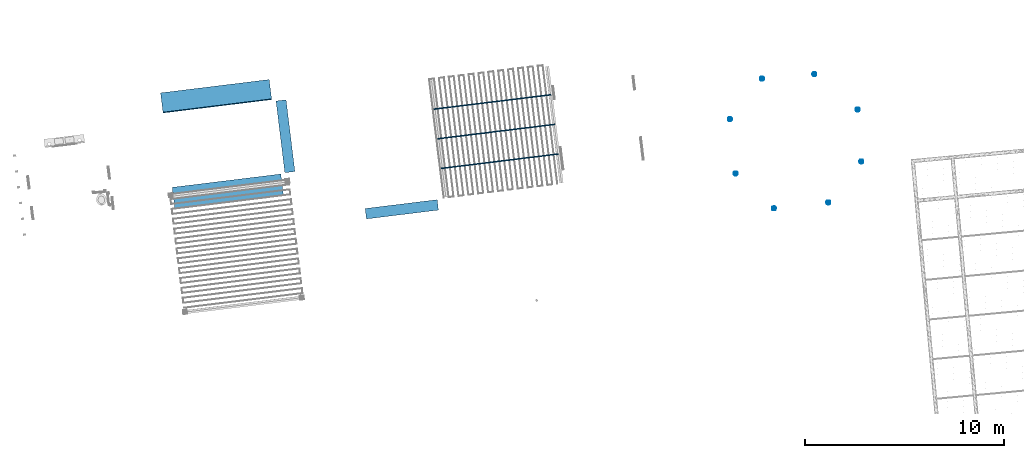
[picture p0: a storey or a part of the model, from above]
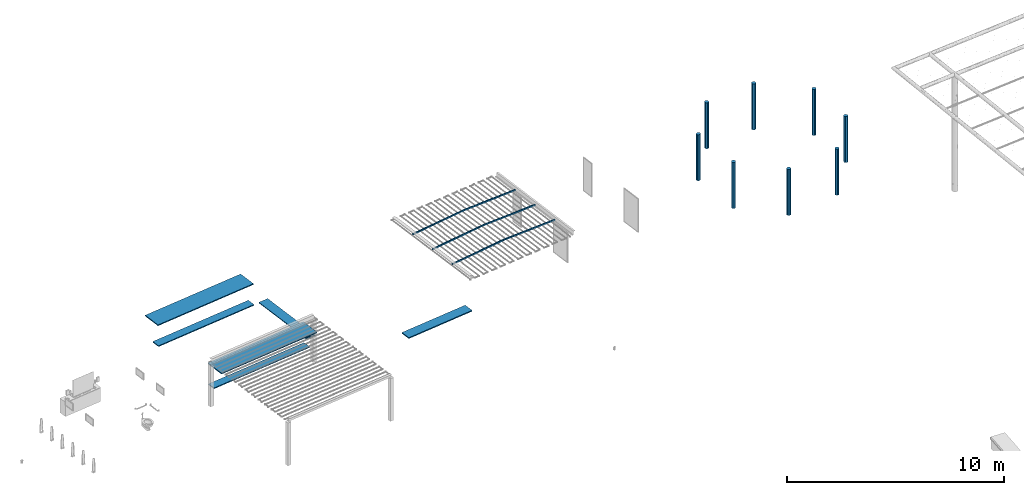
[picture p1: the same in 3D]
Properties of the parts of a building model (IFC2X3), part 1 of 2

# File
Description: ViewDefinition [CoordinationView_V2.0], RevitIdentifiers [VersionGUID: 33807b82-4eea-4ff3-baa8-d16956f95675, NumberOfSaves: 186], CoordinateReference [CoordinateBase: Coordenadas compartilhadas]
File name: JA_Taquaras_EP_R01.rvt
Time: 2023-06-01T09:59:46-03:00
Written by: ODA SDAI 23.12
Made in: Autodesk Revit 24.0.5.432 (PTB) - IFC 24.0.5.432

# IfcProject, JA_Taquaras_EP_R01.rvt
LongName: PROJETO EXECUTIVO; Phase: .

# IfcSite, Default
RefLatitude: -15, -52, 0, -120620; RefLongitude: -47, -55, 0, -114440; RefElevation: 0 m

# IfcBuilding, Projeto
LongName: Projeto
Pset_BuildingCommon - NumberOfStoreys: 5

# IfcBuildingStorey: Nível:8 mm Extremidade superior (5)
In: Projeto
Name | LongName | Elevation (m)
Nível 9 | Nível 9 | -2.58104
Nível 1 | Nível 1 | 0
Primeiro Pavimento | Primeiro Pavimento | 0
Segundo Pavimento | Segundo Pavimento | 3
Cobertura | Cobertura | 10

# IfcBeam: 23.25.30.11.14.14 - VIGA.MADEIRA:5x5 (8)
In: Nível 1
Type - Pset_BeamCommon - IsExternal: no; LoadBearing: yes
Material: .ET - EST METALICA
Pset_BeamCommon - Reference: 5x5; Span: 6 m; Slope: 0 deg
Pset_QuantityTakeOff - Reference: 5x5; sets with these values: 2
Name (23.25.30.11.14.14 - VIGA.MADEIRA:5x5:...)
1272677
1272681
1276401
1276405
1568845 | Group: Grupo de modelos:Grupo 6 (membros excluídos):1568625
1568847 | Group: Grupo de modelos:Grupo 6 (membros excluídos):1568625
1583513 | Group: Grupo de modelos:Grupo 6 (membros excluídos):1583293
1583515 | Group: Grupo de modelos:Grupo 6 (membros excluídos):1583293

# IfcBeam: 23.25.30.11.14.14 - VIGA.MADEIRA:5x5 2 (16)
Type - Pset_BeamCommon - IsExternal: no; LoadBearing: yes
Material: .ET - EST METALICA
Pset_BeamCommon - Reference: 5x5 2
Pset_QuantityTakeOff - Reference: 5x5 2; sets with these values: 2
Name (23.25.30.11.14.14 - VIGA.MADEIRA:5x5 2:...) | In | Span (m) | Slope (deg) | Group
1568901 | Primeiro Pavimento | 3 | 2.19526 | Grupo de modelos:Grupo 6 (membros excluídos):1568625
1568903 | Primeiro Pavimento | 3 | 2.19526 | Grupo de modelos:Grupo 6 (membros excluídos):1568625
1568905 | Primeiro Pavimento | 3 | 2.19526 | Grupo de modelos:Grupo 6 (membros excluídos):1568625
1568914 | Primeiro Pavimento | 3 | 2.19526 | Grupo de modelos:Grupo 6 (membros excluídos):1568625
1568916 | Primeiro Pavimento | 3 | 2.19526 | Grupo de modelos:Grupo 6 (membros excluídos):1568625
1568918 | Primeiro Pavimento | 3 | 2.19526 | Grupo de modelos:Grupo 6 (membros excluídos):1568625
1583569 | Nível 9 | 3 | 2.19526 | Grupo de modelos:Grupo 6 (membros excluídos):1583293
1583571 | Nível 9 | 3 | 2.19526 | Grupo de modelos:Grupo 6 (membros excluídos):1583293
1583573 | Nível 9 | 3 | 2.19526 | Grupo de modelos:Grupo 6 (membros excluídos):1583293
1583582 | Nível 9 | 3 | 2.19526 | Grupo de modelos:Grupo 6 (membros excluídos):1583293
1583584 | Nível 9 | 3 | 2.19526 | Grupo de modelos:Grupo 6 (membros excluídos):1583293
1583586 | Nível 9 | 3 | 2.19526 | Grupo de modelos:Grupo 6 (membros excluídos):1583293
1613297 | Nível 1 | 5.95047 | 0.0481941 | Grupo de modelos:Grupo 6 (membros excluídos):1568625
1613686 | Nível 1 | 5.95047 | 0.0481941 | Grupo de modelos:Grupo 6 (membros excluídos):1583293
1617300 | Nível 1 | 5.95047 | 0.0481941 | Grupo de modelos:Grupo 6 (membros excluídos):1568625
1617335 | Nível 1 | 5.95047 | 0.0481941 | Grupo de modelos:Grupo 6 (membros excluídos):1583293

# IfcBuildingElementProxy: Arvore simplificada:Arvore simplificada (20)
In: Nível 1
Type - Material: <Unnamed>
Pset_BuildingElementProxyCommon - Reference: Arvore simplificada; sets with these values: 2
Name (Arvore simplificada:Arvore simplificada:...)
1117187
1128409
1128419
1128431
1128439
1128447
1128455
1128463
1128471
1128479
1128489
1128499
1128509
1128519
1128527
1128539
1128549
1128559
1128567
1128575

# IfcBuildingElementProxy: DURAVIT_218209-DuraStyle-Basic-floor-mounted-toi:Vaso sanitário (4)
In: Nível 1
Type - Material: 218209-DuraStyle Basic floor-mounted toilet - durastyle-basic-floor-mounted-toilet-218209 - Color
Pset_BuildingElementProxyCommon - Reference: Vaso sanitário; sets with these values: 2
Name (DURAVIT_218209-DuraStyle-Basic-floor-mounted-toi:Vaso sanitário:...)
1442904
1442907
1442910
1442913

# IfcBuildingElementProxy: Dispositivos elétricos 1:Dispositivos elétricos 1, Dispositivos elétricos 1:Dispositivos elétricos 1:1149304
In: Nível 9
Type - Material: 3D Equip. 10
Pset_BuildingElementProxyCommon - Reference: Dispositivos elétricos 1; sets with these values: 2

# IfcBuildingElementProxy: Massa 1:Massa 1, Massa 1:Massa 1:1149017
In: Nível 9
Type - Material: <Unnamed>
Pset_BuildingElementProxyCommon - Reference: Massa 1; sets with these values: 2

# IfcBuildingElementProxy: Mobiliário 2:Mobiliário 2, Mobiliário 2:Mobiliário 2:1530271
In: Nível 9
Type - Material: cacao
Pset_BuildingElementProxyCommon - Reference: Mobiliário 2; sets with these values: 2

# IfcBuildingElementProxy: Modelos genéricos 1:Modelos genéricos 1, Modelos genéricos 1:Modelos genéricos 1:1151902
In: Nível 9
Type - Material: metal estrutura
Pset_BuildingElementProxyCommon - Reference: Modelos genéricos 1; sets with these values: 2

# IfcBuildingElementProxy: Modelos genéricos 2:Modelos genéricos 2, Modelos genéricos 2:Modelos genéricos 2:1620208
In: Nível 9
Type - Material: .ET - EST METALICA
Pset_BuildingElementProxyCommon - Reference: Modelos genéricos 2; sets with these values: 2
Pset_ProvisionForVoid - Width: 0.19 m; Height: 0.192261 m; Depth: 0.192261 m

# IfcBuildingElementProxy: Modelos genéricos 3:Modelos genéricos 3, Modelos genéricos 3:Modelos genéricos 3:1680973
In: Nível 9
Type - Material: Vidro
Pset_BuildingElementProxyCommon - Reference: Modelos genéricos 3; sets with these values: 2
Pset_ProvisionForVoid - Width: 0.005 m; Height: 1.2 m; Depth: 1.2 m

# IfcBuildingElementProxy: Vegetação Genérica:Árvore (21)
Type - Material: Tronco, Vegetação
Pset_BuildingElementProxyCommon - Reference: Árvore; sets with these values: 2
Name (Vegetação Genérica:Árvore:...) | In
1433401 | Nível 1
1433469 | Nível 1
1433492 | Nível 1
1433971 | Nível 1
1434128 | Nível 1
1434138 | Nível 1
1434273 | Nível 1
1434547 | Nível 1
1434555 | Nível 1
1434704 | Nível 1
1434777 | Nível 1
1434796 | Nível 1
1434824 | Nível 1
1434863 | Nível 1
1434968 | Nível 1
1435148 | Nível 1
1435156 | Nível 1
1461229 | Nível 1
1461309 | Nível 1
1474241 | Nível 1
1711147 | Primeiro Pavimento

# IfcColumn: Coreto:Coreto, Coreto:Coreto:1116822
In: Nível 9
Type - PredefinedType: COLUMN; Material: <Unnamed>, Cerejeira
Type - Pset_ColumnCommon - IsExternal: no; LoadBearing: yes
Material: Cerejeira
Pset_ColumnCommon - Reference: Coreto
Pset_QuantityTakeOff - Reference: Coreto; sets with these values: 2

# IfcCovering: Forro composto:Plano (4)
In: Segundo Pavimento
Type - PredefinedType: CEILING
Type - Pset_CoveringCommon - TotalThickness: 0.057 m
Material: Camada de suporte de metal 0.045 m, Placa de gesso de parede 0.012 m
Pset_CoveringCommon - Reference: Plano; sets with these values: 2
Name (Forro composto:Plano:...) | Group
1095109 | Grupo de modelos:ED1:1098709
1104618 | Grupo de modelos:ED6:1103990
1104683 | Grupo de modelos:ED6:1103990
1105033 | Grupo de modelos:ED6:1103990

# IfcCurtainWall: Parede cortina:Vitrine (5)
In: Nível 1
Type - Pset_CurtainWallCommon - IsExternal: yes
Pset_CurtainWallCommon - Reference: Vitrine
Pset_QuantityTakeOff - Reference: Vitrine
Name (Parede cortina:Vitrine:...)
1573662 | Group: Grupo de modelos:quiosque3:1573406
1574445
1596405
1626986
1627316

# IfcDistributionPort (15)
Description: Flow
Name | FlowDirection
InPort_1444392_1 | SINK
OutPort_1444392_2 | SOURCE
InPort_1675223_5 | SINK
OutPort_1675223_6 | SOURCE
InPort_1675503_5 | SINK
OutPort_1675503_6 | SOURCE
InPort_1675512_5 | SINK
OutPort_1675512_6 | SOURCE
InPort_1675577_5 | SINK
OutPort_1675577_6 | SOURCE
InPort_1675769_5 | SINK
OutPort_1675769_6 | SOURCE
InPort_1680600_1 | SINK
InPort_1680650_1 | SINK
InPort_1746563_1 | SINK

# IfcDoor: M_Folha única:0800 x 2100mm, M_Folha única:0800 x 2100mm:1297596
In: Nível 1
Type - ParameterTakesPrecedence: no; Sizeable: no; Material: Porta - Batente, Porta - Painel
Type - Pset_DoorCommon - IsExternal: no; ThermalTransmittance: 3.7021 kg/K/s3
OverallHeight: 2.1 m; OverallWidth: 0.8 m
Pset_DoorCommon - Reference: 0800 x 2100mm
Pset_QuantityTakeOff - Reference: 0800 x 2100mm

# IfcDoor: M_Folha única:0915 x 2032mm, M_Folha única:0915 x 2032mm:1300241
In: Nível 1
Type - ParameterTakesPrecedence: no; Sizeable: no; Material: Porta - Batente, Porta - Painel
Type - Pset_DoorCommon - IsExternal: no; ThermalTransmittance: 3.7021 kg/K/s3
OverallHeight: 2.032 m; OverallWidth: 0.915 m
Pset_DoorCommon - Reference: 0915 x 2032mm
Pset_QuantityTakeOff - Reference: 0915 x 2032mm

# IfcDoor: M_porta pvc:0800 x 2100mm (4)
In: Nível 1
Type - ParameterTakesPrecedence: no; Sizeable: no; Material: Porta - Batente, Porta - Painel
Type - Pset_DoorCommon - IsExternal: no; ThermalTransmittance: 3.7021 kg/K/s3
OverallHeight: 2.1 m; OverallWidth: 0.8 m
Pset_DoorCommon - Reference: 0800 x 2100mm
Pset_QuantityTakeOff - Reference: 0800 x 2100mm
Name (M_porta pvc:0800 x 2100mm:...)
1306554
1306905
1306987
1306988

# IfcElementAssembly: Sistema de viga estrutural:Sistema de estrutura estrutural (4)
PredefinedType: BEAM_GRID
Pset_QuantityTakeOff - Reference: Sistema de estrutura estrutural
Name (Sistema de viga estrutural:Sistema de estrutura estrutural:...) | In | Group
1568896 | Primeiro Pavimento | Grupo de modelos:Grupo 6 (membros excluídos):1568625
1568909 | Primeiro Pavimento | Grupo de modelos:Grupo 6 (membros excluídos):1568625
1583564 | Nível 9 | Grupo de modelos:Grupo 6 (membros excluídos):1583293
1583577 | Nível 9 | Grupo de modelos:Grupo 6 (membros excluídos):1583293

# IfcFlowTerminal: Deca_Bacia Duna_P.707_Caixa Acoplada:Dual Flux 3 lpf / 6 lpf - Branco GE17 (5)
In: Nível 1
Type - Material: <Unnamed>, Deca GE17 Branco Gelo Cerâmica
Type - Pset_ManufacturerTypeInformation - Manufacturer: Deca
Pset_DistributionFlowElementCommon - Reference: Dual Flux 3 lpf / 6 lpf - Branco GE17; sets with these values: 2
Name (Deca_Bacia Duna_P.707_Caixa Acoplada:Dual Flux 3 lpf / 6 lpf - Branco GE17:...)
1675223
1675503
1675512
1675577
1675769

# IfcFlowTerminal: Deca_Shared_Assento_P.707:Assento termofixo slow close e easy clean - Branco GE17 (5)
In: Nível 1
Type - Material: Deca GE17 Branco Gelo Poliéster
Type - Pset_ManufacturerTypeInformation - Manufacturer: Deca
Pset_DistributionFlowElementCommon - Reference: Assento termofixo slow close e easy clean - Branco GE17; sets with these values: 2
Name (Deca_Shared_Assento_P.707:Assento termofixo slow close e easy clean - Branco GE17:...)
1675224
1675504
1675513
1675578
1675770

# IfcFlowTerminal: Deca_Shared_Caixa Acoplada_P.707:Dual Flux 3 lpf / 6 lpf - Branco GE17 (5)
In: Nível 1
Type - Material: Deca GE17 Branco Gelo Cerâmica
Type - Pset_ManufacturerTypeInformation - Manufacturer: Deca
Pset_DistributionFlowElementCommon - Reference: Dual Flux 3 lpf / 6 lpf - Branco GE17; sets with these values: 2
Name (Deca_Shared_Caixa Acoplada_P.707:Dual Flux 3 lpf / 6 lpf - Branco GE17:...)
1675225
1675505
1675514
1675579
1675771

# IfcFlowTerminal: Deca_Torneira_Link_1167.C.LNK:1167.C.LNK (3)
Type - Material: Deca CR10 Cromado Metal
Type - Pset_ManufacturerTypeInformation - Manufacturer: Deca
Pset_DistributionFlowElementCommon - Reference: 1167.C.LNK; sets with these values: 2
Name (Deca_Torneira_Link_1167.C.LNK:1167.C.LNK:...) | In
1680600 | Cobertura
1680650 | Cobertura
1746563 | Nível 1

# IfcFlowTerminal: M_Pia de cozinha-Ilha:Pia para banheiro (3)
In: Nível 1
Type - Material: Metal - Aço, Polido
Pset_DistributionFlowElementCommon - Reference: Pia para banheiro; sets with these values: 2
Name (M_Pia de cozinha-Ilha:Pia para banheiro:...)
1440380
1440467
1440518

# IfcFlowTerminal: Plumbing-Gravity-Toilets-Sloan-Valve-WETS-40294211:Vaso sanitário PNE, Plumbing-Gravity-Toilets-Sloan-Valve-WETS-40294211:Vaso sanitário PNE:1444392
In: Nível 1
Type - Material: Sloan Valve - Vitreous China - White, Sloan Valve - Finish - Polished Chrome
Type - Pset_ManufacturerTypeInformation - Manufacturer: Sloan Valve
Classification: D2010 Uniformat (Uniformat)
Pset_DistributionFlowElementCommon - Reference: Vaso sanitário PNE; sets with these values: 2

# IfcFlowTerminal: Sanitary_Basins_DURAVIT_236375-Sink:Pia adaptada PNE, Sanitary_Basins_DURAVIT_236375-Sink:Pia adaptada PNE:1441920
In: Nível 1
Type - Material: 236375 Sink - white-tulip-sink-236375 - White Alpin
Pset_DistributionFlowElementCommon - Reference: Pia adaptada PNE; sets with these values: 2

# IfcFlowTerminal: UK_Grab Rail Horizontal:2D Disabled Toilet (2)
In: Nível 9
Type - Material: Metal - White powder coated
Pset_DistributionFlowElementCommon - Reference: 2D Disabled Toilet; sets with these values: 2
Name (UK_Grab Rail Horizontal:2D Disabled Toilet:...)
1665409
1665930

# IfcFlowTerminal: Vigas2:Vigas, Vigas2:Vigas:1583611
In: Nível 9
Type - Material: .ET - EST METALICA
Pset_DistributionFlowElementCommon - Reference: Vigas; sets with these values: 2
Group: Grupo de modelos:Grupo 6 (membros excluídos):1583293

# IfcFlowTerminal: Vigas3:Vigas, Vigas3:Vigas:1583635
In: Nível 9
Type - Material: .ET - EST METALICA
Pset_DistributionFlowElementCommon - Reference: Vigas; sets with these values: 2
Group: Grupo de modelos:Grupo 6 (membros excluídos):1583293

# IfcFlowTerminal: Vigas4:Vigas, Vigas4:Vigas:1568943
In: Nível 9
Type - Material: .ET - EST METALICA
Pset_DistributionFlowElementCommon - Reference: Vigas; sets with these values: 2
Group: Grupo de modelos:Grupo 6 (membros excluídos):1568625

# IfcFlowTerminal: Vigas5:Vigas, Vigas5:Vigas:1568967
In: Nível 9
Type - Material: .ET - EST METALICA
Pset_DistributionFlowElementCommon - Reference: Vigas; sets with these values: 2
Group: Grupo de modelos:Grupo 6 (membros excluídos):1568625

# IfcFlowTerminal: _Produtos_Arq_Bib_Floor_mounted_flush-valve_toilet_w_3-piece_grab_bars_4834:17" Seat Height, _Produtos_Arq_Bib_Floor_mounted_flush-valve_toilet_w_3-piece_grab_bars_4834:17" Seat Height:1669619
In: Nível 9
Type - Material: Porcelain - Ivory, Laminate - Ivory,Matte, Metal - Steel, Polished
Classification: D2010110 Uniformat (Uniformat)
Pset_DistributionFlowElementCommon - Reference: 17" Seat Height; sets with these values: 2

# IfcFurnishingElement: Bancadas banheiro2:Bancadas banheiro, Bancadas banheiro2:Bancadas banheiro:1681031
In: Nível 9
Type - Material: Plastico preto fosco, Aço, GRANITO, Madeira ripada
Pset_QuantityTakeOff - Reference: Bancadas banheiro

# IfcFurnishingElement: Banco2:Banco com encosto 2, Banco2:Banco com encosto 2:1472425
In: Nível 1
Type - Material: Metal, Madeira
Type - Pset_ManufacturerTypeInformation - Manufacturer: MMcité
Pset_QuantityTakeOff - Reference: Banco com encosto 2

# IfcFurnishingElement: CADEIRAADIRONDAQUE:Adirondack Chair (24)
In: Nível 1
Type - Material: NewTechWood - Antique Atlantic
Type - Pset_ManufacturerTypeInformation - Manufacturer: NewTechWood
Pset_QuantityTakeOff - Reference: Adirondack Chair
Name (CADEIRAADIRONDAQUE:Adirondack Chair:...)
1426978
1427038
1427043
1427048
1427064
1427069
1427074
1427079
1427092
1427099
1427104
1427109
1514125 | Group: Grupo de modelos:Grupo de matrizes 3:1514393
1514407 | Group: Grupo de modelos:Grupo de matrizes 3:1514408
1514420 | Group: Grupo de modelos:Grupo de matrizes 3:1514421
1514458 | Group: Grupo de modelos:Grupo de matrizes 3:1514459
1514460 | Group: Grupo de modelos:Grupo de matrizes 3:1514461
1514462 | Group: Grupo de modelos:Grupo de matrizes 3:1514463
1514476 | Group: Grupo de modelos:Grupo de matrizes 3:1514477
1514478 | Group: Grupo de modelos:Grupo de matrizes 3:1514479
1514480 | Group: Grupo de modelos:Grupo de matrizes 3:1514481
1514494 | Group: Grupo de modelos:Grupo de matrizes 3:1514495
1514496 | Group: Grupo de modelos:Grupo de matrizes 3:1514497
1514498 | Group: Grupo de modelos:Grupo de matrizes 3:1514499

# IfcFurnishingElement: CS110:Lixeira Simples (6)
In: Nível 1
Type - Material: Metal, Aço, Metal(1)
Type - Pset_ManufacturerTypeInformation - Manufacturer: MMcité
Pset_QuantityTakeOff - Reference: Lixeira Simples
Name (CS110:Lixeira Simples:...)
1444702
1444705
1444708
1472524
1473167
1473223

# IfcFurnishingElement: Iluminação de chão:Iluminação de chão (19)
Type - Material: Aço, <Unnamed>
Pset_QuantityTakeOff - Reference: Iluminação de chão
Name (Iluminação de chão:Iluminação de chão:...) | In
1435394 | Nível 1
1436348 | Nível 1
1437167 | Nível 9
1437235 | Nível 1
1437324 | Nível 1
1437332 | Nível 1
1437391 | Nível 1
1437732 | Nível 9
1437844 | Nível 1
1438212 | Nível 9
1438383 | Nível 1
1438557 | Nível 1
1438599 | Nível 1
1438659 | Nível 9
1438667 | Nível 1
1438708 | Nível 9
1438717 | Nível 1
1461230 | Nível 9
1461311 | Nível 9

# IfcFurnishingElement: Landscaping_Other_Byarums-Bruk_Arkus:Biciletário (12)
Type - Material: ByarumsBruk-Natur(RawAluminium)
Type - Pset_ElementShading - Color: Grey
Type - Pset_ManufacturerTypeInformation - ModelReference: n/a; Manufacturer: Byarums Bruk
Type - Pset_ProductRequirements - Name: Byarums-Bruk_Arkus; Category: Cycle stands and lockers
Pset_ManufacturerOccurrence - BarCode: n/a; SerialNumber: n/a
Pset_QuantityTakeOff - Reference: Biciletário
Name (Landscaping_Other_Byarums-Bruk_Arkus:Biciletário:...) | In
1444721 | Nível 1
1444752 | Nível 1
1444760 | Nível 1
1444768 | Nível 1
1444776 | Nível 1
1444784 | Nível 1
1472692 | Nível 9
1472823 | Nível 9
1472833 | Nível 9
1472843 | Nível 9
1472851 | Nível 9
1472859 | Nível 9

# IfcFurnishingElement: Mobiliário 1:Mobiliário 1, Mobiliário 1:Mobiliário 1:1150153
In: Primeiro Pavimento
Type - Material: 3D Mecanismo 01 Equip. 02
Pset_QuantityTakeOff - Reference: Mobiliário 1

# IfcFurnishingElement: Mobiliário 3:Mobiliário 2, Mobiliário 3:Mobiliário 2:1530515
In: Nível 9
Type - Material: Camada de suporte de metal
Pset_QuantityTakeOff - Reference: Mobiliário 2

# IfcFurnishingElement: Mobiliário 4:Mobiliário 2, Mobiliário 4:Mobiliário 2:1530638
In: Nível 9
Type - Material: Camada de suporte de metal, cacao
Pset_QuantityTakeOff - Reference: Mobiliário 2

# IfcFurnishingElement: Pergolado2:Pergolado, Pergolado2:Pergolado:1616212
In: Nível 9
Type - Material: Aço
Pset_QuantityTakeOff - Reference: Pergolado
Group: Grupo de modelos:Grupo 6 (membros excluídos):1583293

# IfcFurnishingElement: Pergolado3:Pergolado, Pergolado3:Pergolado:1615888
In: Nível 9
Type - Material: Aço
Pset_QuantityTakeOff - Reference: Pergolado
Group: Grupo de modelos:Grupo 6 (membros excluídos):1568625

# IfcFurnishingElement: lareiran:lareiran (3)
In: Nível 1
Type - Material: <Unnamed>
Pset_QuantityTakeOff - Reference: lareiran
Name (lareiran:lareiran:...)
1417715
1417724
1417743

# IfcFurnishingElement: play genérico:play genérico, play genérico:play genérico:1318031
In: Nível 1
Type - Material: <Unnamed>
Pset_QuantityTakeOff - Reference: play genérico

# IfcFurnishingElement: poste ja8:poste ja8 (7)
In: Nível 1
Type - Material: <Unnamed>
Pset_QuantityTakeOff - Reference: poste ja8
Name (poste ja8:poste ja8:...)
1460368
1460384
1460458
1461030
1461407
1461445
1461491

# IfcMember: Montante retangular:50 x 150mm (110)
In: Nível 1
Type - PredefinedType: MULLION; Material: Alumín.
Type - Pset_MemberCommon - IsExternal: no
Pset_MemberCommon - Reference: 50 x 150mm
Pset_QuantityTakeOff - Reference: 50 x 150mm
Name (Montante retangular:50 x 150mm:...) | Span (m)
1573681 | 0.833761 | Pset_MemberCommon - IsExternal: yes; Group: Grupo de modelos:quiosque3:1573406
1573682 | 0.858761 | Pset_MemberCommon - IsExternal: yes; Group: Grupo de modelos:quiosque3:1573406
1573683 | 0.858761 | Pset_MemberCommon - IsExternal: yes; Group: Grupo de modelos:quiosque3:1573406
1573686 | 2.18297 | Pset_MemberCommon - IsExternal: yes; Group: Grupo de modelos:quiosque3:1573406
1573687 | 2.18297 | Pset_MemberCommon - IsExternal: yes; Group: Grupo de modelos:quiosque3:1573406
1573694 | 0.653049 | Pset_MemberCommon - IsExternal: yes; Group: Grupo de modelos:quiosque3:1573406
1573695 | 1.14182 | Pset_MemberCommon - IsExternal: yes; Group: Grupo de modelos:quiosque3:1573406
1573696 | 0.833761 | Pset_MemberCommon - IsExternal: yes; Group: Grupo de modelos:quiosque3:1573406
1573697 | 0.858761 | Pset_MemberCommon - IsExternal: yes; Group: Grupo de modelos:quiosque3:1573406
1573698 | 0.858761 | Pset_MemberCommon - IsExternal: yes; Group: Grupo de modelos:quiosque3:1573406
1573747 | 0.833761 | Pset_MemberCommon - IsExternal: yes; Group: Grupo de modelos:quiosque3:1573406
1573748 | 0.833761 | Pset_MemberCommon - IsExternal: yes; Group: Grupo de modelos:quiosque3:1573406
1573749 | 2.18297 | Pset_MemberCommon - IsExternal: yes; Group: Grupo de modelos:quiosque3:1573406
1573750 | 0.645326 | Pset_MemberCommon - IsExternal: yes; Group: Grupo de modelos:quiosque3:1573406
1582803 | 1.02924 | Pset_MemberCommon - IsExternal: yes; Group: Grupo de modelos:quiosque3:1573406
1582804 | 1.02101 | Pset_MemberCommon - IsExternal: yes; Group: Grupo de modelos:quiosque3:1573406
1582805 | 1.02924 | Pset_MemberCommon - IsExternal: yes; Group: Grupo de modelos:quiosque3:1573406
1582806 | 1.05755 | Pset_MemberCommon - IsExternal: yes; Group: Grupo de modelos:quiosque3:1573406
1582807 | 2.18297 | Pset_MemberCommon - IsExternal: yes; Group: Grupo de modelos:quiosque3:1573406
1582809 | 0.169852 | Pset_MemberCommon - IsExternal: yes; Group: Grupo de modelos:quiosque3:1573406
1626107 | 0.162129 | Pset_MemberCommon - IsExternal: yes; Group: Grupo de modelos:quiosque3:1573406
1626108 | 2.18297 | Pset_MemberCommon - IsExternal: yes; Group: Grupo de modelos:quiosque3:1573406
1574464 | 0.833761
1574465 | 0.858761
1574466 | 0.858761
1574469 | 2.18297
1574470 | 2.18297
1574477 | 0.653049
1574478 | 1.14182
1574479 | 0.833761
1574480 | 0.858761
1574481 | 0.858761
1574493 | 0.833761
1574494 | 0.833761
1574495 | 2.18297
1574496 | 0.645326
1582627 | 1.02924
1582628 | 1.02101
1582629 | 1.02924
1582630 | 1.05755
1582631 | 2.18297
1582633 | 0.169852
1626023 | 0.162129
1626024 | 2.18297
1596418 | 0.833761
1596419 | 0.858761
1596420 | 0.858761
1596421 | 2.20797
1596422 | 2.20797
1596427 | 0.653049
1596428 | 1.14182
1596429 | 0.833761
1596430 | 0.858761
1596431 | 0.858761
1596467 | 0.833761
1596468 | 0.833761
1596469 | 2.20797
1596470 | 0.645326
1596475 | 1.02924
1596476 | 1.02101
1596477 | 1.02924
1596478 | 1.05755
1596479 | 2.20797
1596481 | 0.169852
1626013 | 0.162129
1626014 | 2.20797
1626999 | 0.833761
1627000 | 0.858761
1627001 | 0.858761
1627002 | 2.18297
1627003 | 2.18297
1627008 | 0.653049
1627009 | 1.14182
1627010 | 0.833761
1627011 | 0.858761
1627012 | 0.858761
1627016 | 0.833761
1627017 | 0.833761
1627018 | 2.18297
1627019 | 0.645326
1627024 | 1.02924
1627025 | 1.02101
1627026 | 1.02924
1627027 | 1.05755
1627028 | 2.18297
1627029 | 0.169852
1627030 | 0.162129
1627031 | 2.18297
1627329 | 0.833761
1627330 | 0.858761
1627331 | 0.858761
1627332 | 2.18297
1627333 | 2.18297
1627338 | 0.653049
1627339 | 1.14182
1627340 | 0.833761
1627341 | 0.858761
1627342 | 0.858761
1627346 | 0.833761
1627347 | 0.833761
1627348 | 2.18297
1627349 | 0.645326
1627354 | 1.02924
1627355 | 1.02101
1627356 | 1.02924
1627357 | 1.05755
1627358 | 2.18297
1627359 | 0.169852
1627360 | 0.162129
1627361 | 2.18297

# IfcOpeningElement: Opening (265)
In: Nível 1
Name | Reference | sets with these values
Parede básica:JA_Aluminio:1095195:1 | JA_Aluminio | 2 | Group: Grupo de modelos:ED1:1098709
Parede básica:JA_Aluminio:1095199:1 | JA_Aluminio | 2 | Group: Grupo de modelos:ED1:1098709
Parede básica:JA_Aluminio:1095203:1 | JA_Aluminio | 2 | Group: Grupo de modelos:ED1:1098709
Parede básica:JA_Aluminio:1095207:1 | JA_Aluminio | 2 | Group: Grupo de modelos:ED1:1098709
Parede básica:JA_Aluminio:1095211:1 | JA_Aluminio | 2 | Group: Grupo de modelos:ED1:1098709
Parede básica:JA_Aluminio:1095215:1 | JA_Aluminio | 2 | Group: Grupo de modelos:ED1:1098709
Parede básica:JA_Aluminio:1095229:1 | JA_Aluminio | 2 | Group: Grupo de modelos:ED1:1098709
Parede básica:JA_Aluminio:1095233:1 | JA_Aluminio | 2 | Group: Grupo de modelos:ED1:1098709
Parede básica:JA_Aluminio:1095237:1 | JA_Aluminio | 2 | Group: Grupo de modelos:ED1:1098709
Parede básica:JA_Aluminio:1095241:1 | JA_Aluminio | 2 | Group: Grupo de modelos:ED1:1098709
Parede básica:JA_Aluminio:1095251:1 | JA_Aluminio | 2 | Group: Grupo de modelos:ED1:1098709
2 x Parede básica:JA_Aluminio:713331 | JA_Aluminio | 2 | Group: Grupo de modelos:ED6:1103990
Parede básica:JA_Aluminio:1104897:1 | JA_Aluminio | 2 | Group: Grupo de modelos:ED6:1103990
Parede básica:JA_Aluminio:1104898:1 | JA_Aluminio | 2 | Group: Grupo de modelos:ED6:1103990
Parede básica:JA_Aluminio:1104899:1 | JA_Aluminio | 2 | Group: Grupo de modelos:ED6:1103990
Parede básica:JA_Aluminio:1104900:1 | JA_Aluminio | 2 | Group: Grupo de modelos:ED6:1103990
Parede básica:JA_Aluminio:1104901:1 | JA_Aluminio | 2 | Group: Grupo de modelos:ED6:1103990
Parede básica:JA_Aluminio:1104902:1 | JA_Aluminio | 2 | Group: Grupo de modelos:ED6:1103990
Parede básica:JA_Aluminio:1104903:1 | JA_Aluminio | 2 | Group: Grupo de modelos:ED6:1103990
Parede básica:JA_Aluminio:1104904:1 | JA_Aluminio | 2 | Group: Grupo de modelos:ED6:1103990
Parede básica:JA_Aluminio:1104905:1 | JA_Aluminio | 2 | Group: Grupo de modelos:ED6:1103990
Parede básica:JA_Aluminio:1104906:1 | JA_Aluminio | 2 | Group: Grupo de modelos:ED6:1103990
Parede básica:15cm:1105429:1 | 15cm | 2 | Group: Grupo de modelos:ED4:1105388
Parede básica:15cm:1105430:1 | 15cm | 2 | Group: Grupo de modelos:ED4:1105388
Parede básica:15cm:1105431:1 | 15cm | 2 | Group: Grupo de modelos:ED4:1105388
Parede básica:15cm:1105434:1 | 15cm | 2 | Group: Grupo de modelos:ED4:1105388
11 x Piso:Basalto 40x80:1313126 | Basalto 40x80 | 2
Parede básica:15cm 2:1179894:1 | 15cm 2 | 2
Parede básica:15cm 2:1179894:2 | 15cm 2 | 2
Parede básica:15cm 2:1179894:3 | 15cm 2 | 2
Parede básica:15cm 2:1179894:4 | 15cm 2 | 2
Parede básica:15cm 2:1179894:5 | 15cm 2 | 2
Parede básica:15cm 2:1179894:6 | 15cm 2 | 2
Parede básica:15cm 2:1179894:7 | 15cm 2 | 2
Parede básica:15cm 2:1179894:8 | 15cm 2 | 2
Parede básica:15cm 2:1179894:9 | 15cm 2 | 2
Parede básica:15cm 2:1179894:10 | 15cm 2 | 2
Parede básica:15cm 2:1179894:11 | 15cm 2 | 2
Parede básica:15cm 2:1179894:12 | 15cm 2 | 2
Parede básica:15cm 2:1179894:13 | 15cm 2 | 2
Parede básica:15cm 2:1179894:14 | 15cm 2 | 2
Parede básica:15cm 2:1179894:15 | 15cm 2 | 2
Parede básica:15cm 2:1179894:16 | 15cm 2 | 2
Parede básica:15cm 2:1179894:17 | 15cm 2 | 2
Parede básica:15cm 2:1179894:18 | 15cm 2 | 2
Parede básica:15cm 2:1179894:19 | 15cm 2 | 2
Parede básica:15cm 2:1179894:20 | 15cm 2 | 2
Parede básica:15cm 2:1179894:21 | 15cm 2 | 2
Parede básica:15cm 2:1179894:22 | 15cm 2 | 2
Parede básica:15cm 2:1179894:23 | 15cm 2 | 2
Parede básica:15cm 2:1179894:24 | 15cm 2 | 2
Parede básica:15cm 2:1179894:25 | 15cm 2 | 2
Parede básica:15cm 2:1179894:26 | 15cm 2 | 2
Parede básica:15cm 2:1179894:27 | 15cm 2 | 2
Parede básica:15cm 2:1179943:1 | 15cm 2 | 2
Parede básica:15cm 2:1179943:2 | 15cm 2 | 2
Parede básica:15cm 2:1179943:3 | 15cm 2 | 2
Parede básica:15cm 2:1179943:4 | 15cm 2 | 2
Parede básica:15cm 2:1179943:5 | 15cm 2 | 2
Parede básica:15cm 2:1179943:6 | 15cm 2 | 2
Parede básica:15cm 2:1179943:7 | 15cm 2 | 2
Parede básica:15cm 2:1179943:8 | 15cm 2 | 2
Parede básica:15cm 2:1179943:9 | 15cm 2 | 2
Parede básica:15cm 2:1179943:10 | 15cm 2 | 2
Parede básica:15cm 2:1179943:11 | 15cm 2 | 2
Parede básica:15cm 2:1179943:12 | 15cm 2 | 2
Parede básica:15cm 2:1179943:13 | 15cm 2 | 2
Parede básica:15cm 2:1179943:14 | 15cm 2 | 2
Parede básica:15cm 2:1179943:15 | 15cm 2 | 2
Parede básica:15cm 2:1179943:16 | 15cm 2 | 2
Parede básica:15cm 2:1179943:17 | 15cm 2 | 2
Parede básica:15cm 2:1179943:18 | 15cm 2 | 2
Parede básica:15cm 2:1179943:19 | 15cm 2 | 2
Parede básica:15cm 2:1179943:20 | 15cm 2 | 2
Parede básica:15cm 2:1179943:21 | 15cm 2 | 2
Parede básica:15cm 2:1179943:22 | 15cm 2 | 2
Parede básica:15cm 2:1179943:23 | 15cm 2 | 2
Parede básica:15cm 2:1179943:24 | 15cm 2 | 2
Parede básica:15cm 2:1179943:25 | 15cm 2 | 2
Parede básica:15cm 2:1179943:26 | 15cm 2 | 2
Parede básica:15cm 2:1179943:27 | 15cm 2 | 2
Parede básica:15cm 2:1180014:1 | 15cm 2 | 2
Parede básica:15cm 2:1180014:2 | 15cm 2 | 2
Parede básica:15cm 2:1180014:3 | 15cm 2 | 2
Parede básica:15cm 2:1180014:4 | 15cm 2 | 2
Parede básica:15cm 2:1180014:5 | 15cm 2 | 2
Parede básica:15cm 2:1180014:6 | 15cm 2 | 2
Parede básica:15cm 2:1180014:7 | 15cm 2 | 2
Parede básica:15cm 2:1180014:8 | 15cm 2 | 2
Parede básica:15cm 2:1180014:9 | 15cm 2 | 2
Parede básica:15cm 2:1180014:10 | 15cm 2 | 2
Parede básica:15cm 2:1180014:11 | 15cm 2 | 2
Parede básica:15cm 2:1180014:12 | 15cm 2 | 2
Parede básica:15cm 2:1180014:13 | 15cm 2 | 2
Parede básica:15cm 2:1180014:14 | 15cm 2 | 2
Parede básica:15cm 2:1180014:15 | 15cm 2 | 2
Parede básica:15cm 2:1180014:16 | 15cm 2 | 2
Parede básica:15cm 2:1180014:17 | 15cm 2 | 2
Parede básica:15cm 2:1180014:18 | 15cm 2 | 2
Parede básica:15cm 2:1180014:19 | 15cm 2 | 2
Parede básica:15cm 2:1180014:20 | 15cm 2 | 2
Parede básica:15cm 2:1180014:21 | 15cm 2 | 2
Parede básica:15cm 2:1180014:22 | 15cm 2 | 2
Parede básica:15cm 2:1180014:23 | 15cm 2 | 2
Parede básica:15cm 2:1180014:24 | 15cm 2 | 2
Parede básica:15cm 2:1180014:25 | 15cm 2 | 2
Parede básica:15cm 2:1180014:26 | 15cm 2 | 2
Parede básica:15cm 2:1180014:27 | 15cm 2 | 2
Parede básica:15cm 2:1180143:1 | 15cm 2 | 2
Parede básica:15cm 2:1180143:2 | 15cm 2 | 2
Parede básica:15cm 2:1180143:3 | 15cm 2 | 2
Parede básica:15cm 2:1180143:4 | 15cm 2 | 2
Parede básica:15cm 2:1180143:5 | 15cm 2 | 2
Parede básica:15cm 2:1180143:6 | 15cm 2 | 2
Parede básica:15cm 2:1180143:7 | 15cm 2 | 2
Parede básica:15cm 2:1180143:8 | 15cm 2 | 2
Parede básica:15cm 2:1180143:9 | 15cm 2 | 2
Parede básica:15cm 2:1180143:10 | 15cm 2 | 2
Parede básica:15cm 2:1180143:11 | 15cm 2 | 2
Parede básica:15cm 2:1180143:12 | 15cm 2 | 2
Parede básica:15cm 2:1180143:13 | 15cm 2 | 2
Parede básica:15cm 2:1180143:14 | 15cm 2 | 2
Parede básica:15cm 2:1180143:15 | 15cm 2 | 2
Parede básica:15cm 2:1180143:16 | 15cm 2 | 2
Parede básica:15cm 2:1180143:17 | 15cm 2 | 2
Parede básica:15cm 2:1180143:18 | 15cm 2 | 2
Parede básica:15cm 2:1180143:19 | 15cm 2 | 2
Parede básica:15cm 2:1180143:20 | 15cm 2 | 2
Parede básica:15cm 2:1180143:21 | 15cm 2 | 2
Parede básica:15cm 2:1180143:22 | 15cm 2 | 2
Parede básica:15cm 2:1180143:23 | 15cm 2 | 2
Parede básica:15cm 2:1180143:24 | 15cm 2 | 2
Parede básica:15cm 2:1180143:25 | 15cm 2 | 2
Parede básica:15cm 2:1180143:26 | 15cm 2 | 2
Parede básica:15cm 2:1180143:27 | 15cm 2 | 2
Parede básica:15cm 2:1180186:1 | 15cm 2 | 2
Parede básica:15cm 2:1180186:2 | 15cm 2 | 2
Parede básica:15cm 2:1180186:3 | 15cm 2 | 2
Parede básica:15cm 2:1180186:4 | 15cm 2 | 2
Parede básica:15cm 2:1180186:5 | 15cm 2 | 2
Parede básica:15cm 2:1180186:6 | 15cm 2 | 2
Parede básica:15cm 2:1180186:7 | 15cm 2 | 2
Parede básica:15cm 2:1180186:8 | 15cm 2 | 2
Parede básica:15cm 2:1180186:9 | 15cm 2 | 2
Parede básica:15cm 2:1180186:10 | 15cm 2 | 2
Parede básica:15cm 2:1180186:11 | 15cm 2 | 2
Parede básica:15cm 2:1180186:12 | 15cm 2 | 2
Parede básica:15cm 2:1180186:13 | 15cm 2 | 2
Parede básica:15cm 2:1180186:14 | 15cm 2 | 2
Parede básica:15cm 2:1180186:15 | 15cm 2 | 2
Parede básica:15cm 2:1180186:16 | 15cm 2 | 2
Parede básica:15cm 2:1180186:17 | 15cm 2 | 2
Parede básica:15cm 2:1180186:18 | 15cm 2 | 2
Parede básica:15cm 2:1180186:19 | 15cm 2 | 2
Parede básica:15cm 2:1180186:20 | 15cm 2 | 2
Parede básica:15cm 2:1180186:21 | 15cm 2 | 2
Parede básica:15cm 2:1180186:22 | 15cm 2 | 2
Parede básica:15cm 2:1180186:23 | 15cm 2 | 2
Parede básica:15cm 2:1180186:24 | 15cm 2 | 2
Parede básica:15cm 2:1180186:25 | 15cm 2 | 2
Parede básica:15cm 2:1180186:26 | 15cm 2 | 2
Parede básica:15cm 2:1180250:1 | 15cm 2 | 2
Parede básica:15cm 2:1180250:2 | 15cm 2 | 2
Parede básica:15cm 2:1180250:3 | 15cm 2 | 2
Parede básica:15cm 2:1180250:4 | 15cm 2 | 2
Parede básica:15cm 2:1180250:5 | 15cm 2 | 2
Parede básica:15cm 2:1180250:6 | 15cm 2 | 2
Parede básica:15cm 2:1180250:7 | 15cm 2 | 2
Parede básica:15cm 2:1180250:8 | 15cm 2 | 2
Parede básica:15cm 2:1180250:9 | 15cm 2 | 2
Parede básica:15cm 2:1180250:10 | 15cm 2 | 2
Parede básica:15cm 2:1180250:11 | 15cm 2 | 2
Parede básica:15cm 2:1180250:12 | 15cm 2 | 2
Parede básica:15cm 2:1180250:13 | 15cm 2 | 2
Parede básica:15cm 2:1180250:14 | 15cm 2 | 2
Parede básica:15cm 2:1180250:15 | 15cm 2 | 2
Parede básica:15cm 2:1180250:16 | 15cm 2 | 2
Parede básica:15cm 2:1180250:17 | 15cm 2 | 2
Parede básica:15cm 2:1180250:18 | 15cm 2 | 2
Parede básica:15cm 2:1180250:19 | 15cm 2 | 2
Parede básica:15cm 2:1180250:20 | 15cm 2 | 2
Parede básica:15cm 2:1180250:21 | 15cm 2 | 2
Parede básica:15cm 2:1180250:22 | 15cm 2 | 2
Parede básica:15cm 2:1180250:23 | 15cm 2 | 2
Parede básica:15cm 2:1180250:24 | 15cm 2 | 2
Parede básica:15cm 2:1180250:25 | 15cm 2 | 2
Parede básica:15cm 2:1180250:26 | 15cm 2 | 2
Parede básica:15cm 2:1180250:27 | 15cm 2 | 2
Piso:Zoysia japonica:542695 | Zoysia japonica | 2
Piso:Banco de concreto:1131619 | Banco de concreto | 2
Piso:Piso cacão:1310116 | Piso cacão | 2
6 x Parede básica:7,5cm:1295113 | 7,5cm | 2
Parede básica:7,5cm:1304541:1 | 7,5cm | 2
Parede básica:15cm 2:1409784:1 | 15cm 2 | 2
Parede básica:15cm 2:1409784:2 | 15cm 2 | 2
Parede básica:15cm 2:1409784:3 | 15cm 2 | 2
Parede básica:15cm 2:1409784:4 | 15cm 2 | 2
Parede básica:15cm 2:1409784:5 | 15cm 2 | 2
Parede básica:15cm 2:1409784:6 | 15cm 2 | 2
Parede básica:15cm 2:1409784:7 | 15cm 2 | 2
Parede básica:15cm 2:1409784:8 | 15cm 2 | 2
Parede básica:15cm 2:1409928:1 | 15cm 2 | 2
Parede básica:15cm 2:1409928:2 | 15cm 2 | 2
Parede básica:15cm 2:1409928:3 | 15cm 2 | 2
Parede básica:15cm 2:1409928:4 | 15cm 2 | 2
Parede básica:15cm 2:1409928:5 | 15cm 2 | 2
Parede básica:15cm 2:1409928:6 | 15cm 2 | 2
Parede básica:15cm 2:1409928:7 | 15cm 2 | 2
Parede básica:15cm 2:1409928:8 | 15cm 2 | 2
Parede básica:15cm 2:1415796:1 | 15cm 2 | 2
Parede básica:15cm 2:1415796:2 | 15cm 2 | 2
Parede básica:15cm 2:1415796:3 | 15cm 2 | 2
Parede básica:15cm 2:1415796:4 | 15cm 2 | 2
Parede básica:15cm 2:1415796:5 | 15cm 2 | 2
Parede básica:15cm 2:1415796:6 | 15cm 2 | 2
Parede básica:15cm 2:1415796:7 | 15cm 2 | 2
Parede básica:15cm 2:1415796:8 | 15cm 2 | 2
Parede básica:15cm 2:1415796:9 | 15cm 2 | 2
Parede básica:15cm 2:1415827:1 | 15cm 2 | 2
Parede básica:15cm 2:1415827:2 | 15cm 2 | 2
Parede básica:15cm 2:1415827:3 | 15cm 2 | 2
Parede básica:15cm 2:1415827:4 | 15cm 2 | 2
Parede básica:15cm 2:1415827:5 | 15cm 2 | 2
Parede básica:15cm 2:1415827:6 | 15cm 2 | 2
Parede básica:15cm 2:1415827:7 | 15cm 2 | 2
Parede básica:15cm 2:1415827:8 | 15cm 2 | 2
Parede básica:15cm 4:1508168:1 | 15cm 4 | 2
Parede básica:15cm 4:1508168:2 | 15cm 4 | 2
Parede básica:15cm 4:1510847:1 | 15cm 4 | 2
Parede básica:15cm 4:1510847:2 | 15cm 4 | 2
Parede básica:15cm 4:1511041:1 | 15cm 4 | 2
Parede básica:15cm 4:1511041:2 | 15cm 4 | 2
Parede básica:15cm 4:1511193:1 | 15cm 4 | 2
Parede básica:15cm 4:1511193:2 | 15cm 4 | 2
9 x Piso:Basalto Flameado 20x10cm:1313109 | Basalto Flameado 20x10cm | 2
M_Folha única:0915 x 2032mm:1300241:1
M_Folha única:0800 x 2100mm:1297596:1
M_porta pvc:0800 x 2100mm:1306988:1
M_porta pvc:0800 x 2100mm:1306987:1
M_porta pvc:0800 x 2100mm:1306905:1
M_porta pvc:0800 x 2100mm:1306554:1

# IfcPlate: Painel do sistema:Envidraçado (44)
In: Nível 1
Type - PredefinedType: CURTAIN_PANEL; Material: Vidro
Type - Pset_PlateCommon - IsExternal: no; ThermalTransmittance: 6.7069 kg/K/s3
Pset_PlateCommon - Reference: Envidraçado
Pset_QuantityTakeOff - Reference: Envidraçado
Name (Painel do sistema:Envidraçado:...)
1568892 | Pset_PlateCommon - IsExternal: yes; Group: Grupo de modelos:Grupo 6 (membros excluídos):1568625
1568890 | Pset_PlateCommon - IsExternal: yes; Group: Grupo de modelos:Grupo 6 (membros excluídos):1568625
1573674 | Group: Grupo de modelos:quiosque3:1573406
1573676 | Group: Grupo de modelos:quiosque3:1573406
1573678 | Group: Grupo de modelos:quiosque3:1573406
1573743 | Group: Grupo de modelos:quiosque3:1573406
1573689 | Group: Grupo de modelos:quiosque3:1573406
1573690 | Group: Grupo de modelos:quiosque3:1573406
1573691 | Group: Grupo de modelos:quiosque3:1573406
1573744 | Group: Grupo de modelos:quiosque3:1573406
1574457
1574459
1574461
1574489
1574472
1574473
1574474
1574490
1583560 | Group: Grupo de modelos:Grupo 6 (membros excluídos):1583293
1583558 | Group: Grupo de modelos:Grupo 6 (membros excluídos):1583293
1596413
1596415
1596417
1596465
1596424
1596425
1596426
1596466
1626994
1626996
1626998
1627014
1627005
1627006
1627007
1627015
1627324
1627326
1627328
1627344
1627335
1627336
1627337
1627345

# IfcRoof: Telhado básico:Genérico - 400 mm (24)
Material: NBS_Betafence_GreenRAL6005 0.4 m
Pset_QuantityTakeOff - Reference: Genérico - 400 mm
Pset_RoofCommon - IsExternal: yes; Reference: Genérico - 400 mm
Name (Telhado básico:Genérico - 400 mm:...) | In | ProjectedArea (m2) | TotalArea (m2) | Group
1081228 | Segundo Pavimento | 168.902 | 195.031 | Grupo de modelos:EDS3:1098941
1081440 | Segundo Pavimento | 140.257 | 171.223 | Grupo de modelos:EDS3:1098941
1081521 | Segundo Pavimento | 142.461 | 164.5 | Grupo de modelos:EDS3:1098941
1081801 | Segundo Pavimento | 241.341 | 278.677 | Grupo de modelos:EDS3:1098941
1082092 | Segundo Pavimento | 75.3865 | 75.4324 | Grupo de modelos:EDS3:1098941
1082758 | Segundo Pavimento | 113.358 | 130.894 | Grupo de modelos:EDS3:1098941
1082834 | Segundo Pavimento | 174.013 | 200.933 | Grupo de modelos:EDE2:1098817
1095029 | Segundo Pavimento | 165.7 | 182.83 | Grupo de modelos:ED1:1098709
1104526 | Segundo Pavimento | 157.692 | 233.367 | Grupo de modelos:ED6:1103990
1104541 | Segundo Pavimento | 67.0908 | 116.969 | Grupo de modelos:ED6:1103990
1104607 | Segundo Pavimento | 142.636 | 151.79 | Grupo de modelos:ED6:1103990
1104627 | Segundo Pavimento | 281.498 | 299.564 | Grupo de modelos:ED6:1103990
1104639 | Segundo Pavimento | 163.622 | 174.123 | Grupo de modelos:ED6:1103990
1104670 | Segundo Pavimento | 237.407 | 252.643 | Grupo de modelos:ED6:1103990
1104692 | Segundo Pavimento | 172.198 | 183.249 | Grupo de modelos:ED6:1103990
1104821 | Segundo Pavimento | 84.3316 | 87.3065 | Grupo de modelos:ED6:1103990
1104835 | Nível 1 | 25.8353 | 27.4933 | Grupo de modelos:ED6:1103990
1104881 | Segundo Pavimento | 84.3316 | 87.3065 | Grupo de modelos:ED6:1103990
1104923 | Nível 1 | 98.305 | 101.773 | Grupo de modelos:ED6:1103990
1104949 | Segundo Pavimento | 295.409 | 305.83 | Grupo de modelos:ED6:1103990
1105436 | Primeiro Pavimento | 127.844 | 136.048 | Grupo de modelos:ED4:1105388
1105444 | Primeiro Pavimento | 74.5416 | 79.3256 | Grupo de modelos:ED4:1105388
1105594 | Primeiro Pavimento | 148.463 | 171.43 | Grupo de modelos:ED5:1105566
1116088 | Nível 1 | 38.314 | 40.7729

# IfcRoof: Vidraça inclinada:Vidraça inclinada (2)
In: Nível 1
Type - Pset_CurtainWallCommon - IsExternal: yes
Pset_QuantityTakeOff - Reference: Vidraça inclinada
Pset_RoofCommon - IsExternal: yes; Reference: Vidraça inclinada; ProjectedArea: 33.7008 m2
Name (Vidraça inclinada:Vidraça inclinada:...) | Group
1568885 | Grupo de modelos:Grupo 6 (membros excluídos):1568625
1583553 | Grupo de modelos:Grupo 6 (membros excluídos):1583293

# IfcSlab: Piso:Areia, Piso:Areia:1255865
In: Nível 1
Type - PredefinedType: FLOOR
Type - Pset_SlabCommon - IsExternal: yes; ThermalTransmittance: 1.675 kg/K/s3
Material: Areia
Pset_QuantityTakeOff - Reference: Areia; sets with these values: 2
Pset_SlabCommon - LoadBearing: no; PitchAngle: 0 deg; Reference: Areia

# IfcSlab: Piso:Banco de concreto (8)
In: Nível 1
Type - PredefinedType: FLOOR; Material: cacao 0.65 m
Type - Pset_SlabCommon - IsExternal: no
Pset_QuantityTakeOff - Reference: Banco de concreto; sets with these values: 2
Pset_SlabCommon - LoadBearing: no; PitchAngle: 0 deg; Reference: Banco de concreto
Name (Piso:Banco de concreto:...)
1131397
1131675 | Material: cacao
1131965
1139711
1255793
1255884
1258553
1258621

# IfcSlab: Piso:Basalto (2)
In: Nível 1
Type - PredefinedType: FLOOR; Material: Basalto 0.15 m
Type - Pset_SlabCommon - IsExternal: no
Pset_QuantityTakeOff - Reference: Basalto; sets with these values: 2
Pset_SlabCommon - LoadBearing: no; Reference: Basalto
Name (Piso:Basalto:...) | PitchAngle (deg) | Group
1095555 | 2.9969 | Grupo de modelos:ED1:1098709
1105040 | 0 | Grupo de modelos:ED6:1103990

# IfcSlab: Piso:Basalto 40x80 (15)
In: Nível 1
Type - PredefinedType: FLOOR; Material: Piso CAJOI PASSEIO(1) 0.1 m
Type - Pset_SlabCommon - IsExternal: no; ThermalTransmittance: 12 kg/K/s3
Pset_QuantityTakeOff - Reference: Basalto 40x80; sets with these values: 2
Pset_SlabCommon - LoadBearing: no; Reference: Basalto 40x80
Name (Piso:Basalto 40x80:...) | PitchAngle (deg)
1078562 | 0
1079081 | 3.11654
1080120 | 0
1097551 | 0
1097616 | 3.15427
1097711 | 0
1106482 | 0 | Material: Piso CAJOI PASSEIO(1)
1118113 | 3.45504 | Material: Piso CAJOI PASSEIO(1)
1121777 | 0
1122770 | 0
1257463 | 0 | Material: Piso CAJOI PASSEIO(1)
1311295 | 0
1312520 | 0
1314249 | 0
1314249:2 | 0

# IfcSlab: Piso:Basalto Flameado 20x10cm (5)
In: Nível 1
Type - PredefinedType: FLOOR; Material: Piso CAJOI PASSEIO 0.15 m
Type - Pset_SlabCommon - IsExternal: no; ThermalTransmittance: 8 kg/K/s3
Pset_QuantityTakeOff - Reference: Basalto Flameado 20x10cm; sets with these values: 2
Pset_SlabCommon - Reference: Basalto Flameado 20x10cm; LoadBearing: no
Name (Piso:Basalto Flameado 20x10cm:...) | PitchAngle (deg) | Material
1078023 | 3.15455
1503861 | 1.94167 | Piso CAJOI PASSEIO
1503979 | 3.41695 | Piso CAJOI PASSEIO
1724335 | 0
1724398 | 6.84277 | Piso CAJOI PASSEIO

# IfcSlab: Piso:Basalto Flameado 40x20 (Passeio) (6)
In: Nível 1
Type - PredefinedType: FLOOR; Material: Piso CAJOI PASSEIO(1) 0.1 m
Type - Pset_SlabCommon - IsExternal: no; ThermalTransmittance: 12 kg/K/s3
Pset_QuantityTakeOff - Reference: Basalto Flameado 40x20 (Passeio); sets with these values: 2
Pset_SlabCommon - LoadBearing: no; PitchAngle: 0 deg; Reference: Basalto Flameado 40x20 (Passeio)
Name (Piso:Basalto Flameado 40x20 (Passeio):...)
1079758
1097365
1310543
1311156
1311707
1312875

# IfcSlab: Piso:Concreto moldado em loco 225 mm (10)
In: Nível 1
Type - PredefinedType: FLOOR; Material: Concreto, Faixa de areia/cimento 0.05 m, Concreto, Moldado no local 0.175 m
Type - Pset_SlabCommon - IsExternal: no; ThermalTransmittance: 4.64889 kg/K/s3
Pset_QuantityTakeOff - Reference: Concreto moldado em loco 225 mm; sets with these values: 2
Pset_SlabCommon - LoadBearing: no; Reference: Concreto moldado em loco 225 mm
Name (Piso:Concreto moldado em loco 225 mm:...) | PitchAngle (deg)
1096208 | 0
1110481 | 0
1110765 | 0
1111627 | 3.14047
1115271 | 0
1115271:2 | 0
1122399 | 0
1134259 | 0
1134259:2 | 0
1313027 | 0

# IfcSlab: Piso:Degrau de concreto (10)
In: Nível 1
Type - PredefinedType: FLOOR; Material: .Concreto_Laje 0.6 m
Type - Pset_SlabCommon - IsExternal: no; ThermalTransmittance: 1.74333 kg/K/s3
Pset_QuantityTakeOff - Reference: Degrau de concreto; sets with these values: 2
Pset_SlabCommon - LoadBearing: no; PitchAngle: 0 deg; Reference: Degrau de concreto
Name (Piso:Degrau de concreto:...)
1138527
1138604
1139770
1139856
1139920
1139995
1140054
1140128
1255920
1255929

# IfcSlab: Piso:Floração tipo 1 (5)
In: Nível 1
Type - PredefinedType: FLOOR; Material: floração tipo 1 0.04 m, floração tipo 1 0.16 m
Type - Pset_SlabCommon - IsExternal: yes
Pset_QuantityTakeOff - Reference: Floração tipo 1; sets with these values: 2
Pset_SlabCommon - LoadBearing: no; Reference: Floração tipo 1
Name (Piso:Floração tipo 1:...) | Material | PitchAngle (deg)
1107337 | floração tipo 1 | 4.27911
1107401 | floração tipo 1 | 10.3084
1107628 | floração tipo 1 | 3.39185
1107745 | floração tipo 1 | 8.96418
1313447 |  | 0

# IfcSlab: Piso:Floração tipo 2 (12)
In: Nível 1
Type - PredefinedType: FLOOR; Material: floração tipo 2 0.04 m, floração tipo 2 0.16 m
Type - Pset_SlabCommon - IsExternal: yes
Pset_QuantityTakeOff - Reference: Floração tipo 2; sets with these values: 2
Pset_SlabCommon - LoadBearing: no; Reference: Floração tipo 2
Name (Piso:Floração tipo 2:...) | PitchAngle (deg)
1106651 | 0
1106651:2 | 0
1106651:3 | 0
1106651:4 | 0
1106651:5 | 0
1138280 | 6.61781 | Material: floração tipo 2
1140179 | 0
1150334 | 0
1150334:2 | 0
1150334:3 | 0
1150334:4 | 0
1150435 | 0

# IfcSlab: Piso:Genérico 150 mm (16)
Type - PredefinedType: FLOOR; Material: <Unnamed> 0.15 m
Type - Pset_SlabCommon - IsExternal: no
Pset_QuantityTakeOff - Reference: Genérico 150 mm; sets with these values: 2
Pset_SlabCommon - LoadBearing: no; Reference: Genérico 150 mm
Name (Piso:Genérico 150 mm:...) | In | PitchAngle (deg)
1099689 | Nível 1 | 0
1100059 | Nível 1 | 0
1100347 | Nível 1 | 0
1100697 | Nível 1 | 0
1101037 | Nível 1 | 0
1101142 | Nível 1 | 2.9969
1102057 | Nível 1 | 3.03318
1102612 | Nível 1 | 0
1102757 | Nível 1 | 0
1103181 | Nível 1 | 0
1103482 | Nível 1 | 0
1103595 | Nível 1 | 0
1103885 | Nível 1 | 0
1104786 | Segundo Pavimento | 0 | Group: Grupo de modelos:ED6:1103990
1104909 | Nível 1 | 0 | Group: Grupo de modelos:ED6:1103990
1105114 | Nível 1 | 2.9969

# IfcSlab: Piso:Glicinia (7)
In: Nível 1
Type - PredefinedType: FLOOR; Material: floração tipo 2(1) 0.04 m, floração tipo 2 0.16 m
Type - Pset_SlabCommon - IsExternal: yes
Pset_QuantityTakeOff - Reference: Glicinia; sets with these values: 2
Pset_SlabCommon - LoadBearing: no; Reference: Glicinia
Name (Piso:Glicinia:...) | PitchAngle (deg)
1522385 | 3.15455
1522385:2 | 3.15455
1522385:3 | 3.15455
1522385:4 | 3.15455
1522385:5 | 3.15455
1522385:6 | 3.15455
1536900 | 0

# IfcSlab: Piso:Madeira de lei padrão-Acabamento em madeira, Piso:Madeira de lei padrão-Acabamento em madeira:1116162
In: Nível 1
Type - PredefinedType: FLOOR; Material: Piso de carvalho 0.5 m
Type - Pset_SlabCommon - IsExternal: no; ThermalTransmittance: 0.36 kg/K/s3
Pset_QuantityTakeOff - Reference: Madeira de lei padrão-Acabamento em madeira; sets with these values: 2
Pset_SlabCommon - LoadBearing: no; PitchAngle: 0 deg; Reference: Madeira de lei padrão-Acabamento em madeira

# IfcSlab: Piso:Piso Ardósia 3 (4)
In: Nível 1
Type - PredefinedType: FLOOR; Material: .ARQ.RVE - ARDÓSIA 3 0.12 m
Type - Pset_SlabCommon - IsExternal: no
Pset_QuantityTakeOff - Reference: Piso Ardósia 3; sets with these values: 2
Pset_SlabCommon - LoadBearing: no; PitchAngle: 0 deg; Reference: Piso Ardósia 3
Name (Piso:Piso Ardósia 3:...)
1310959
1311113
1311351
1311351:2

# IfcSlab: Piso:Piso cacão (4)
In: Nível 1
Type - PredefinedType: FLOOR; Material: cacao 0.1 m
Type - Pset_SlabCommon - IsExternal: no
Pset_QuantityTakeOff - Reference: Piso cacão; sets with these values: 2
Pset_SlabCommon - LoadBearing: no; Reference: Piso cacão
Name (Piso:Piso cacão:...) | PitchAngle (deg)
1255778 | 10.6438 | Material: cacao
1257746 | 2.13175
1258351 | 2.41545 | Material: cacao
1265797 | 0

# IfcSlab: Piso:Zoysia japonica (5)
In: Nível 1
Type - PredefinedType: FLOOR; Material: Grama-esmeralda 0.04 m, JA_Solo 0.16 m
Type - Pset_SlabCommon - IsExternal: yes
Pset_QuantityTakeOff - Reference: Zoysia japonica; sets with these values: 2
Pset_SlabCommon - LoadBearing: no; Reference: Zoysia japonica
Name (Piso:Zoysia japonica:...) | Material | PitchAngle (deg)
1106722 | Grama-esmeralda, JA_Solo | 0
1255775 | Grama-esmeralda, JA_Solo | 0
1255781 |  | 0
1256023 | Grama-esmeralda, JA_Solo | 5.56719
1256117 | Grama-esmeralda, JA_Solo | 24.6778

# IfcSlab: Piso:faixa (9)
In: Nível 1
Type - PredefinedType: FLOOR; Material: Cristal Pool 0.16 m
Type - Pset_SlabCommon - IsExternal: yes
Pset_QuantityTakeOff - Reference: faixa; sets with these values: 2
Pset_SlabCommon - LoadBearing: no; PitchAngle: 0 deg; Reference: faixa
Name (Piso:faixa:...)
1727673
1727673:2
1727673:3
1727673:4
1727673:5
1727673:6
1727673:7
1727673:8
1727673:9

# IfcSlab: Piso:meio fio de concreto (21)
In: Nível 1
Type - PredefinedType: FLOOR; Material: Concreto moldado In loco 0.12 m
Type - Pset_SlabCommon - IsExternal: no
Pset_QuantityTakeOff - Reference: meio fio de concreto; sets with these values: 2
Pset_SlabCommon - LoadBearing: no; Reference: meio fio de concreto
Name (Piso:meio fio de concreto:...) | PitchAngle (deg)
1096698 | 3.11654 | Material: Concreto moldado In loco
1109747 | 3.15455
1109747:2 | 3.15455
1109747:3 | 3.15455
1109747:4 | 3.15455
1109747:5 | 3.15455
1109747:6 | 3.15455
1109747:7 | 3.15455
1109747:8 | 3.15455
1110631 | 0
1111148 | 0
1111302 | 0
1111302:2 | 0
1111801 | 0
1111801:2 | 0
1111801:3 | 0
1121503 | 0
1121503:2 | 0
1121503:3 | 0
1121503:4 | 0
1121503:5 | 0

# IfcSlab: Pisos 1:Pisos 1, Pisos 1:Pisos 1:1130518
In: Primeiro Pavimento
Type - PredefinedType: FLOOR; Material: Aço
Type - Pset_SlabCommon - IsExternal: no
Pset_QuantityTakeOff - Reference: Pisos 1; sets with these values: 2
Pset_SlabCommon - Reference: Pisos 1

# IfcSlab: Pisos 5:Pisos 1, Pisos 5:Pisos 1:1573613
In: Nível 1
Type - PredefinedType: FLOOR; Material: Aço
Type - Pset_SlabCommon - IsExternal: no
Pset_QuantityTakeOff - Reference: Pisos 1; sets with these values: 2
Pset_SlabCommon - Reference: Pisos 1
Group: Grupo de modelos:quiosque3:1573406

# IfcSlab: Pisos 6:Pisos 1, Pisos 6:Pisos 1:1702629
In: Nível 1
Type - PredefinedType: FLOOR; Material: Aço
Type - Pset_SlabCommon - IsExternal: no
Pset_QuantityTakeOff - Reference: Pisos 1; sets with these values: 2
Pset_SlabCommon - Reference: Pisos 1

# IfcSlab: Pisos 8:Pisos 1, Pisos 8:Pisos 1:1280933
In: Nível 1
Type - PredefinedType: FLOOR; Material: Caixilho
Type - Pset_SlabCommon - IsExternal: no
Pset_QuantityTakeOff - Reference: Pisos 1; sets with these values: 2
Pset_SlabCommon - Reference: Pisos 1

# IfcSlab: Pisos 9:Pisos 1, Pisos 9:Pisos 1:1596368
In: Nível 1
Type - PredefinedType: FLOOR; Material: Placa de gesso de parede
Type - Pset_SlabCommon - IsExternal: no
Pset_QuantityTakeOff - Reference: Pisos 1; sets with these values: 2
Pset_SlabCommon - Reference: Pisos 1

# IfcSlab: Telhado básico:Genérico - 400 mm (62)
Type - PredefinedType: ROOF
Type - Pset_SlabCommon - IsExternal: yes
Material: NBS_Betafence_GreenRAL6005 0.4 m
Pset_QuantityTakeOff - Reference: Genérico - 400 mm; sets with these values: 2
Pset_SlabCommon - Reference: Genérico - 400 mm
Name (Telhado básico:Genérico - 400 mm:...) | In | PitchAngle (deg) | Group
2 x 1081228 | Segundo Pavimento | 30 | Grupo de modelos:EDS3:1098941
2 x 1081440 | Segundo Pavimento | 35 | Grupo de modelos:EDS3:1098941
3 x 1081521 | Segundo Pavimento | 30 | Grupo de modelos:EDS3:1098941
5 x 1081801 | Segundo Pavimento | 30 | Grupo de modelos:EDS3:1098941
2 x 1082092 | Segundo Pavimento | 2 | Grupo de modelos:EDS3:1098941
4 x 1082758 | Segundo Pavimento | 30 | Grupo de modelos:EDS3:1098941
6 x 1082834 | Segundo Pavimento | 30 | Grupo de modelos:EDE2:1098817
2 x 1104541 | Segundo Pavimento | 55 | Grupo de modelos:ED6:1103990
4 x 1104607 | Segundo Pavimento | 20 | Grupo de modelos:ED6:1103990
2 x 1104692 | Segundo Pavimento | 20 | Grupo de modelos:ED6:1103990
3 x 1104821 | Segundo Pavimento | 15 | Grupo de modelos:ED6:1103990
1104835 | Nível 1 | 20 | Grupo de modelos:ED6:1103990
4 x 1104881 | Segundo Pavimento | 15 | Grupo de modelos:ED6:1103990
4 x 1104923 | Nível 1 | 15 | Grupo de modelos:ED6:1103990
4 x 1104949 | Segundo Pavimento | 15 | Grupo de modelos:ED6:1103990
2 x 1105436 | Primeiro Pavimento | 20 | Grupo de modelos:ED4:1105388
2 x 1105444 | Primeiro Pavimento | 20 | Grupo de modelos:ED4:1105388
2 x 1105594 | Primeiro Pavimento | 30 | Grupo de modelos:ED5:1105566
8 x 1116088 | Nível 1 | 20

# IfcStair: Escada moldada no local:Escada monolítica 2 (2)
In: Nível 1
ShapeType: STRAIGHT_RUN_STAIR
Pset_QuantityTakeOff - Reference: Escada monolítica 2
Pset_StairCommon - IsExternal: no; Reference: Escada monolítica 2; NumberOfRiser: 3; NumberOfTreads: 2; RiserHeight: 0.166667 m; TreadLength: 0.25 m
Name (Escada moldada no local:Escada:...)
1413330
1416761

# IfcStairFlight: Lance monolítico:Profundidade de 150 mm (2)
In: Nível 1
Type - PredefinedType: STRAIGHT
NumberOfRiser: 3; NumberOfTreads: 2; RiserHeight: 0.546807 m; TreadLength: 0.82021 m; Material: Concreto, Moldado no local
Pset_QuantityTakeOff - Reference: Profundidade de 150 mm
Pset_StairFlightCommon - Reference: Profundidade de 150 mm; NumberOfRiser: 3; NumberOfTreads: 2; RiserHeight: 0.166667 m; TreadLength: 0.25 m; NosingLength: 0 m; TreadLengthAtOffset: 0.25 m; TreadLengthAtInnerSide: 0.25 m
Name (Escada moldada no local:Escada:...) | WalkingLineOffset (m)
1413330 Run 1 | 4.38938
1416761 Run 1 | 4.79644

# IfcWall: Parede básica:15cm (4)
In: Nível 1
Type - PredefinedType: STANDARD; Material: <Unnamed> 0.03 m, <Unnamed> 0.09 m, <Unnamed> 0.03 m
Type - Pset_WallCommon - IsExternal: yes
Pset_QuantityTakeOff - Reference: 15cm; sets with these values: 2
Pset_WallCommon - LoadBearing: no; ExtendToStructure: yes; Reference: 15cm
Name (Parede básica:15cm:...) | Group
1105427 | Grupo de modelos:ED4:1105388
1105433 | Grupo de modelos:ED4:1105388
1105589 | Grupo de modelos:ED5:1105566
1105591 | Grupo de modelos:ED5:1105566

# IfcWall: Parede básica:15cm 2, Parede básica:15cm 2:1511018
In: Nível 1
Type - PredefinedType: STANDARD; Material: .ARQ.PIS - CONTRAPISO.ARMADO 0.01 m
Type - Pset_WallCommon - IsExternal: yes
Pset_QuantityTakeOff - Reference: 15cm 2; sets with these values: 2
Pset_WallCommon - LoadBearing: no; ExtendToStructure: no; Reference: 15cm 2

# IfcWall: Parede básica:JA_Aluminio (9)
In: Nível 1
Type - PredefinedType: STANDARD; Material: Metal 0.01 m
Type - Pset_WallCommon - IsExternal: yes
Pset_QuantityTakeOff - Reference: JA_Aluminio; sets with these values: 2
Pset_WallCommon - LoadBearing: no; Reference: JA_Aluminio
Group: Grupo de modelos:ED6:1103990
Name (Parede básica:JA_Aluminio:...) | ExtendToStructure
1104547 | no
1104565 | no
1104576 | no
1104663 | yes
1104704 | yes
1104707 | yes
1104737 | yes
1104849 | no
1104961 | no

# IfcWall: Paredes 2:Paredes 1, Paredes 2:Paredes 1:1160976
In: Nível 9
Type - Material: Caixilho
Type - Pset_WallCommon - IsExternal: no
Pset_QuantityTakeOff - Reference: Paredes 1; sets with these values: 2
Pset_WallCommon - Reference: Paredes 1

# IfcWallStandardCase: Parede básica:15cm (9)
In: Nível 1
Type - PredefinedType: STANDARD; Material: <Unnamed> 0.03 m, <Unnamed> 0.09 m, <Unnamed> 0.03 m
Type - Pset_WallCommon - IsExternal: yes
Pset_QuantityTakeOff - Reference: 15cm; sets with these values: 2
Pset_WallCommon - LoadBearing: no; ExtendToStructure: yes; Reference: 15cm
Name (Parede básica:15cm:...) | Group
1105428 | Grupo de modelos:ED4:1105388
1105429 | Grupo de modelos:ED4:1105388
1105430 | Grupo de modelos:ED4:1105388
1105431 | Grupo de modelos:ED4:1105388
1105432 | Grupo de modelos:ED4:1105388
1105434 | Grupo de modelos:ED4:1105388
1105449 | Grupo de modelos:ED4:1105388
1105588 | Grupo de modelos:ED5:1105566
1105590 | Grupo de modelos:ED5:1105566

# IfcWallStandardCase: Parede básica:15cm 2 (37)
In: Nível 1
Type - PredefinedType: STANDARD; Material: .ARQ.PIS - CONTRAPISO.ARMADO 0.01 m
Type - Pset_WallCommon - IsExternal: yes
Pset_QuantityTakeOff - Reference: 15cm 2; sets with these values: 2
Pset_WallCommon - LoadBearing: no; ExtendToStructure: no; Reference: 15cm 2
Name (Parede básica:15cm 2:...)
1172626
1172775
1172916
1172990
1173089
1173197
1173953
1174941
1175102
1176481
1176556
1176598
1176666
1176741
1176803
1179894
1179943
1180014
1180143
1180186
1180250
1183897
1183964
1184198
1184247
1409784
1409928
1415796
1415827
1508061
1508633
1508731
1509531
1511028
1511056
1511069
1511092

# IfcWallStandardCase: Parede básica:15cm 3, Parede básica:15cm 3:1176904
In: Nível 1
Type - PredefinedType: STANDARD; Material: 3D Tubo Equip. 05 0.5 m
Type - Pset_WallCommon - IsExternal: yes
Pset_QuantityTakeOff - Reference: 15cm 3; sets with these values: 2
Pset_WallCommon - LoadBearing: no; ExtendToStructure: no; Reference: 15cm 3

# IfcWallStandardCase: Parede básica:15cm 4 (4)
In: Nível 1
Type - PredefinedType: STANDARD; Material: .ARQ.PIS - CONTRAPISO.ARMADO 0.05 m
Type - Pset_WallCommon - IsExternal: yes
Pset_QuantityTakeOff - Reference: 15cm 4; sets with these values: 2
Pset_WallCommon - LoadBearing: no; ExtendToStructure: no; Reference: 15cm 4
Name (Parede básica:15cm 4:...)
1508168
1510847
1511041
1511193

# IfcWallStandardCase: Parede básica:7,5cm (8)
In: Nível 1
Type - PredefinedType: STANDARD; Material: <Unnamed> 0.03 m, <Unnamed> 0.015 m, <Unnamed> 0.03 m
Type - Pset_WallCommon - IsExternal: yes
Pset_QuantityTakeOff - Reference: 7,5cm; sets with these values: 2
Pset_WallCommon - LoadBearing: no; ExtendToStructure: no; Reference: 7,5cm
Name (Parede básica:7,5cm:...)
1281207
1294769
1296857
1299167
1299188
1303960
1304541
1304615

# IfcWallStandardCase: Parede básica:JA_Aluminio (105)
Type - PredefinedType: STANDARD; Material: Metal 0.01 m
Type - Pset_WallCommon - IsExternal: yes
Pset_QuantityTakeOff - Reference: JA_Aluminio; sets with these values: 2
Pset_WallCommon - LoadBearing: no; Reference: JA_Aluminio
Name (Parede básica:JA_Aluminio:...) | In | ExtendToStructure | Group
1081218 | Nível 1 | yes | Grupo de modelos:EDS3:1098941
1081219 | Nível 1 | yes | Grupo de modelos:EDS3:1098941
1081220 | Nível 1 | yes | Grupo de modelos:EDS3:1098941
1081221 | Nível 1 | yes | Grupo de modelos:EDS3:1098941
1081222 | Nível 1 | yes | Grupo de modelos:EDS3:1098941
1081223 | Nível 1 | yes | Grupo de modelos:EDS3:1098941
1081224 | Nível 1 | yes | Grupo de modelos:EDS3:1098941
1081225 | Nível 1 | yes | Grupo de modelos:EDS3:1098941
1081430 | Nível 1 | yes | Grupo de modelos:EDS3:1098941
1081431 | Nível 1 | yes | Grupo de modelos:EDS3:1098941
1081432 | Nível 1 | yes | Grupo de modelos:EDS3:1098941
1081433 | Nível 1 | yes | Grupo de modelos:EDS3:1098941
1081434 | Nível 1 | yes | Grupo de modelos:EDS3:1098941
1081435 | Nível 1 | yes | Grupo de modelos:EDS3:1098941
1081436 | Nível 1 | yes | Grupo de modelos:EDS3:1098941
1081437 | Nível 1 | yes | Grupo de modelos:EDS3:1098941
1081509 | Nível 1 | yes | Grupo de modelos:EDS3:1098941
1081510 | Nível 1 | yes | Grupo de modelos:EDS3:1098941
1081511 | Nível 1 | yes | Grupo de modelos:EDS3:1098941
1081512 | Nível 1 | yes | Grupo de modelos:EDS3:1098941
1081513 | Nível 1 | yes | Grupo de modelos:EDS3:1098941
1081514 | Nível 1 | yes | Grupo de modelos:EDS3:1098941
1081515 | Nível 1 | yes | Grupo de modelos:EDS3:1098941
1081516 | Nível 1 | yes | Grupo de modelos:EDS3:1098941
1081517 | Nível 1 | yes | Grupo de modelos:EDS3:1098941
1081518 | Nível 1 | yes | Grupo de modelos:EDS3:1098941
1081793 | Nível 1 | yes | Grupo de modelos:EDS3:1098941
1081794 | Nível 1 | yes | Grupo de modelos:EDS3:1098941
1081795 | Nível 1 | yes | Grupo de modelos:EDS3:1098941
1081796 | Nível 1 | yes | Grupo de modelos:EDS3:1098941
1081797 | Nível 1 | yes | Grupo de modelos:EDS3:1098941
1081798 | Nível 1 | yes | Grupo de modelos:EDS3:1098941
1082751 | Nível 1 | yes | Grupo de modelos:EDS3:1098941
1082752 | Nível 1 | yes | Grupo de modelos:EDS3:1098941
1082753 | Nível 1 | yes | Grupo de modelos:EDS3:1098941
1082754 | Nível 1 | yes | Grupo de modelos:EDS3:1098941
1082815 | Nível 1 | yes | Grupo de modelos:EDE2:1098817
1082816 | Nível 1 | yes | Grupo de modelos:EDE2:1098817
1082817 | Nível 1 | yes | Grupo de modelos:EDE2:1098817
1082818 | Nível 1 | yes | Grupo de modelos:EDE2:1098817
1082819 | Nível 1 | yes | Grupo de modelos:EDE2:1098817
1082820 | Nível 1 | yes | Grupo de modelos:EDE2:1098817
1082821 | Nível 1 | yes | Grupo de modelos:EDE2:1098817
1082822 | Nível 1 | yes | Grupo de modelos:EDE2:1098817
1082823 | Nível 1 | yes | Grupo de modelos:EDE2:1098817
1082824 | Nível 1 | yes | Grupo de modelos:EDE2:1098817
1082825 | Nível 1 | yes | Grupo de modelos:EDE2:1098817
1082826 | Nível 1 | yes | Grupo de modelos:EDE2:1098817
1095195 | Nível 1 | yes | Grupo de modelos:ED1:1098709
1095199 | Nível 1 | yes | Grupo de modelos:ED1:1098709
1095203 | Nível 1 | yes | Grupo de modelos:ED1:1098709
1095207 | Nível 1 | yes | Grupo de modelos:ED1:1098709
1095211 | Nível 1 | yes | Grupo de modelos:ED1:1098709
1095215 | Nível 1 | yes | Grupo de modelos:ED1:1098709
1095219 | Nível 1 | yes | Grupo de modelos:ED1:1098709
1095229 | Nível 1 | yes | Grupo de modelos:ED1:1098709
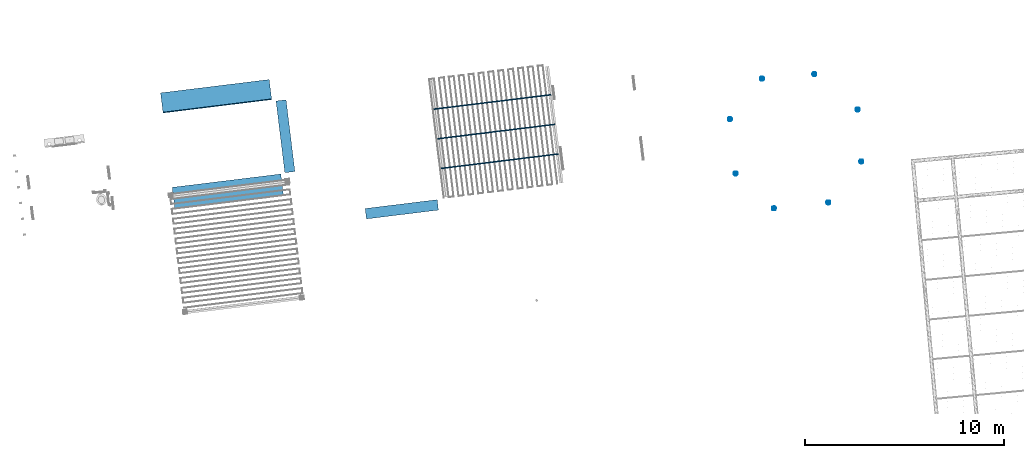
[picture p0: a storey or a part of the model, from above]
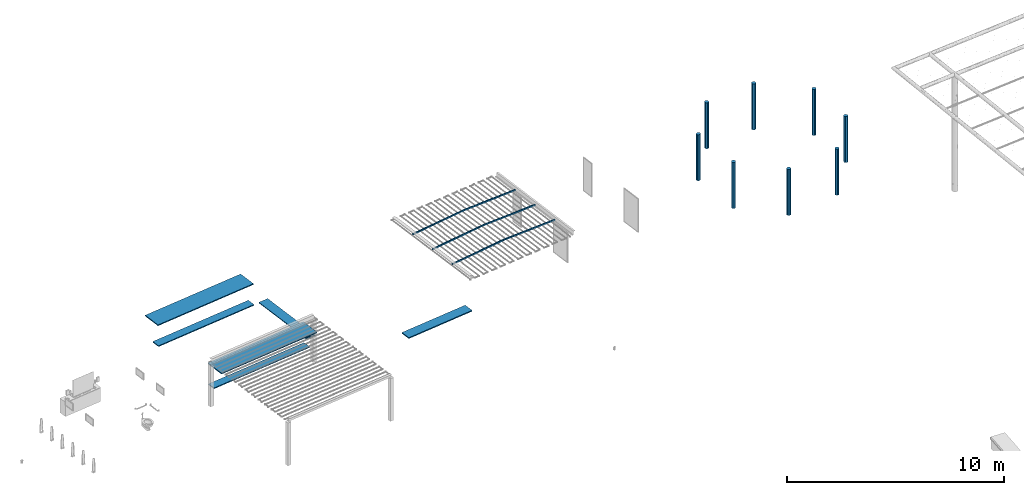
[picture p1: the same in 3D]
Properties of the parts of a building model (IFC2X3), part 2 of 2

# IfcWallStandardCase: Parede básica:JA_Aluminio (105)
Name (Parede básica:JA_Aluminio:...) | In | ExtendToStructure | Group
1095233 | Nível 1 | yes | Grupo de modelos:ED1:1098709
1095237 | Nível 1 | yes | Grupo de modelos:ED1:1098709
1095241 | Nível 1 | yes | Grupo de modelos:ED1:1098709
1095251 | Nível 1 | yes | Grupo de modelos:ED1:1098709
1104560 | Nível 1 | yes | Grupo de modelos:ED6:1103990
1104561 | Nível 1 | yes | Grupo de modelos:ED6:1103990
1104562 | Nível 1 | yes | Grupo de modelos:ED6:1103990
1104622 | Nível 1 | yes | Grupo de modelos:ED6:1103990
1104623 | Nível 1 | yes | Grupo de modelos:ED6:1103990
1104624 | Nível 1 | yes | Grupo de modelos:ED6:1103990
1104636 | Nível 1 | yes | Grupo de modelos:ED6:1103990
1104664 | Nível 1 | yes | Grupo de modelos:ED6:1103990
1104665 | Nível 1 | yes | Grupo de modelos:ED6:1103990
1104666 | Nível 1 | yes | Grupo de modelos:ED6:1103990
1104667 | Nível 1 | yes | Grupo de modelos:ED6:1103990
1104688 | Nível 1 | yes | Grupo de modelos:ED6:1103990
1104689 | Nível 1 | yes | Grupo de modelos:ED6:1103990
1104690 | Nível 1 | yes | Grupo de modelos:ED6:1103990
1104705 | Nível 1 | yes | Grupo de modelos:ED6:1103990
1104706 | Nível 1 | yes | Grupo de modelos:ED6:1103990
1104708 | Nível 1 | yes | Grupo de modelos:ED6:1103990
1104752 | Nível 1 | no | Grupo de modelos:ED6:1103990
1104782 | Nível 1 | no | Grupo de modelos:ED6:1103990
1104783 | Nível 1 | no | Grupo de modelos:ED6:1103990
1104791 | Segundo Pavimento | no | Grupo de modelos:ED6:1103990
1104792 | Segundo Pavimento | no | Grupo de modelos:ED6:1103990
1104793 | Segundo Pavimento | no | Grupo de modelos:ED6:1103990
1104840 | Nível 1 | yes | Grupo de modelos:ED6:1103990
1104841 | Nível 1 | yes | Grupo de modelos:ED6:1103990
1104877 | Nível 1 | yes | Grupo de modelos:ED6:1103990
1104878 | Nível 1 | yes | Grupo de modelos:ED6:1103990
1104879 | Nível 1 | yes | Grupo de modelos:ED6:1103990
1104887 | Nível 1 | yes | Grupo de modelos:ED6:1103990
1104888 | Nível 1 | yes | Grupo de modelos:ED6:1103990
1104889 | Nível 1 | yes | Grupo de modelos:ED6:1103990
1104890 | Nível 1 | yes | Grupo de modelos:ED6:1103990
1104897 | Nível 1 | no | Grupo de modelos:ED6:1103990
1104898 | Nível 1 | no | Grupo de modelos:ED6:1103990
1104899 | Nível 1 | no | Grupo de modelos:ED6:1103990
1104900 | Nível 1 | no | Grupo de modelos:ED6:1103990
1104901 | Nível 1 | no | Grupo de modelos:ED6:1103990
1104902 | Nível 1 | no | Grupo de modelos:ED6:1103990
1104903 | Nível 1 | no | Grupo de modelos:ED6:1103990
1104904 | Nível 1 | no | Grupo de modelos:ED6:1103990
1104905 | Nível 1 | no | Grupo de modelos:ED6:1103990
1104906 | Nível 1 | no | Grupo de modelos:ED6:1103990
1104962 | Nível 1 | yes | Grupo de modelos:ED6:1103990
1104963 | Nível 1 | yes | Grupo de modelos:ED6:1103990
1104964 | Nível 1 | yes | Grupo de modelos:ED6:1103990

# IfcWindow: Janelas 1:Janelas 1, Janelas 1:Janelas 1:1581150
In: Nível 9
Type - ParameterTakesPrecedence: no; Sizeable: no; Material: Vidro, .Aço escovado
Type - Pset_WindowCommon - IsExternal: no
OverallHeight: 7.18041 m; OverallWidth: 30.9777 m
Pset_QuantityTakeOff - Reference: Janelas 1
Pset_WindowCommon - Reference: Janelas 1
